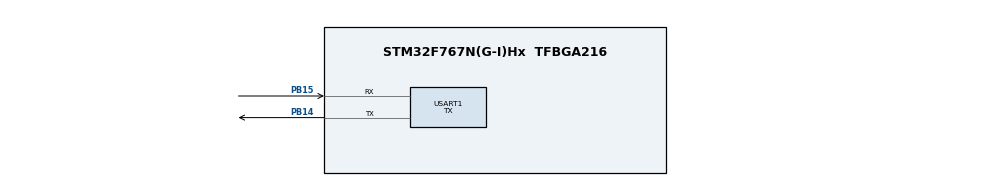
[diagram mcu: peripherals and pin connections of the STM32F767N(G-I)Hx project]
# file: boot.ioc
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CORTEX_M7.CPU_DCache=Disabled
CORTEX_M7.CPU_ICache=Disabled
CORTEX_M7.PREFETCH_ENABLE=0
Mcu.Family=STM32F7
Mcu.Name=STM32F767N(G-I)Hx
Mcu.Package=TFBGA216
NVIC.PriorityGroup=NVIC_PRIORITYGROUP_4
PB14.Mode=Asynchronous
PB14.Signal=USART1_TX
PB15.Mode=Asynchronous
PB15.Signal=USART1_RX
ProjectManager.HeapSize=0x200
ProjectManager.StackSize=0x400
ProjectManager.TargetToolchain=STM32CubeIDE
RCC.AHBFreq_Value=16000000
RCC.APB1CLKDivider=RCC_HCLK_DIV4
RCC.APB1Freq_Value=4000000
RCC.APB1TimFreq_Value=8000000
RCC.APB2CLKDivider=RCC_HCLK_DIV2
RCC.APB2Freq_Value=8000000
RCC.APB2TimFreq_Value=16000000
RCC.CortexFreq_Value=16000000
RCC.HCLKFreq_Value=16000000
RCC.HSE_VALUE=25000000
RCC.HSI_VALUE=16000000
RCC.LSE_VALUE=32768
RCC.PLLM=25
RCC.PLLN=432
RCC.SYSCLKFreq_VALUE=16000000
RCC.USBFreq_Value=138240000
RCC.VCOOutputFreq_Value=276480000
USART1.Mode=MODE_TX
USART1.VirtualMode-Asynchronous=VM_ASYNC
board=custom

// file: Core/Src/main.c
/* USER CODE BEGIN Header */
/**
  ******************************************************************************
  * @file           : main.c
  * @brief          : Main program body
  ******************************************************************************
  * @attention
  *
  * Copyright (c) 2024 STMicroelectronics.
  * All rights reserved.
  *
  * This software is licensed under terms that can be found in the LICENSE file
  * in the root directory of this software component.
  * If no LICENSE file comes with this software, it is provided AS-IS.
  *
  ******************************************************************************
  */
/* USER CODE END Header */
#include "main.h"

/* USER CODE BEGIN Includes */
#include <stdio.h>
/* USER CODE END Includes */

UART_HandleTypeDef huart1;

void SystemClock_Config(void);
static void MX_GPIO_Init(void);
static void MX_USART1_UART_Init(void);

/* USER CODE BEGIN 0 */
int __io_putchar(int ch)
{
  /* Place your implementation of fputc here */
  /* e.g. write a character to the USART1 and Loop until the end of transmission */
  HAL_UART_Transmit(&huart1, (uint8_t *)&ch, 1, 0xFFFF);

  return ch;
}

/* USER CODE END 0 */

int main(void)
{
/* Enable the CPU Cache */

  /* Enable I-Cache---------------------------------------------------------*/
  SCB_EnableICache();

  /* Enable D-Cache---------------------------------------------------------*/
  SCB_EnableDCache();

  /* MCU Configuration--------------------------------------------------------*/

  /* Reset of all peripherals, Initializes the Flash interface and the Systick. */
  HAL_Init();

  /* Configure the system clock */
  SystemClock_Config();

  /* Initialize all configured peripherals */
  MX_GPIO_Init();
  MX_USART1_UART_Init();

  /* Infinite loop */
  while (1)
  {

    /* USER CODE BEGIN 3 */
    printf("Hello\r\n");
    HAL_Delay(1000);
  }
  /* USER CODE END 3 */
}

void SystemClock_Config(void)
{
  RCC_OscInitTypeDef RCC_OscInitStruct = {0};
  RCC_ClkInitTypeDef RCC_ClkInitStruct = {0};

  /** Configure the main internal regulator output voltage
  */
  __HAL_RCC_PWR_CLK_ENABLE();
  __HAL_PWR_VOLTAGESCALING_CONFIG(PWR_REGULATOR_VOLTAGE_SCALE1);

  /** Initializes the RCC Oscillators according to the specified parameters
  * in the RCC_OscInitTypeDef structure.
  */
  RCC_OscInitStruct.OscillatorType = RCC_OSCILLATORTYPE_HSE;
  RCC_OscInitStruct.HSEState = RCC_HSE_ON;
  RCC_OscInitStruct.PLL.PLLState = RCC_PLL_ON;
  RCC_OscInitStruct.PLL.PLLSource = RCC_PLLSOURCE_HSE;
  RCC_OscInitStruct.PLL.PLLM = 25;
  RCC_OscInitStruct.PLL.PLLN = 432;
  RCC_OscInitStruct.PLL.PLLP = RCC_PLLP_DIV2;
  RCC_OscInitStruct.PLL.PLLQ = 2;
  RCC_OscInitStruct.PLL.PLLR = 2;
  if (HAL_RCC_OscConfig(&RCC_OscInitStruct) != HAL_OK)
  {
    Error_Handler();
  }

  /** Activate the Over-Drive mode
  */
  if (HAL_PWREx_EnableOverDrive() != HAL_OK)
  {
    Error_Handler();
  }

  /** Initializes the CPU, AHB and APB buses clocks
  */
  RCC_ClkInitStruct.ClockType = RCC_CLOCKTYPE_HCLK|RCC_CLOCKTYPE_SYSCLK
                              |RCC_CLOCKTYPE_PCLK1|RCC_CLOCKTYPE_PCLK2;
  RCC_ClkInitStruct.SYSCLKSource = RCC_SYSCLKSOURCE_PLLCLK;
  RCC_ClkInitStruct.AHBCLKDivider = RCC_SYSCLK_DIV1;
  RCC_ClkInitStruct.APB1CLKDivider = RCC_HCLK_DIV4;
  RCC_ClkInitStruct.APB2CLKDivider = RCC_HCLK_DIV2;

  if (HAL_RCC_ClockConfig(&RCC_ClkInitStruct, FLASH_LATENCY_7) != HAL_OK)
  {
    Error_Handler();
  }
}

static void MX_USART1_UART_Init(void)
{

  huart1.Instance = USART1;
  huart1.Init.BaudRate = 115200;
  huart1.Init.WordLength = UART_WORDLENGTH_8B;
  huart1.Init.StopBits = UART_STOPBITS_1;
  huart1.Init.Parity = UART_PARITY_NONE;
  huart1.Init.Mode = UART_MODE_TX;
  huart1.Init.HwFlowCtl = UART_HWCONTROL_NONE;
  huart1.Init.OverSampling = UART_OVERSAMPLING_16;
  huart1.Init.OneBitSampling = UART_ONE_BIT_SAMPLE_DISABLE;
  huart1.AdvancedInit.AdvFeatureInit = UART_ADVFEATURE_NO_INIT;
  if (HAL_UART_Init(&huart1) != HAL_OK)
  {
    Error_Handler();
  }

}

static void MX_GPIO_Init(void)
{

  /* GPIO Ports Clock Enable */
  __HAL_RCC_GPIOH_CLK_ENABLE();
  __HAL_RCC_GPIOB_CLK_ENABLE();

}

void Error_Handler(void)
{
  __disable_irq();
  while (1)
  {
  }
}
